# TIEHI/TIELO for osu025, generated by make_tie_cells.py from upstream INVX1.
VERSION 5.4 ;
NAMESCASESENSITIVE ON ;
BUSBITCHARS "[]" ;
DIVIDERCHAR "/" ;

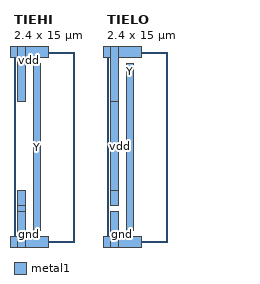
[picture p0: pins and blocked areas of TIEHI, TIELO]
MACRO TIEHI
  CLASS  CORE ;
  FOREIGN TIEHI 0.000 0.000 ;
  ORIGIN 0.000 0.000 ;
  SIZE 2.400 BY 15.000 ;
  SYMMETRY X Y  ;
  SITE core ;
  PIN gnd
    DIRECTION INOUT ;
    USE GROUND ;
    SHAPE ABUTMENT ;
    PORT
      LAYER metal1 ;
        RECT 0.300 2.850 0.900 4.050 ;
        RECT 0.300 2.400 0.900 2.850 ;
        RECT 0.300 -0.450 0.900 2.400 ;
        RECT -0.300 -0.450 2.700 0.450 ;
    END
  END gnd
  PIN Y
    DIRECTION OUTPUT ;
    PORT
      LAYER metal1 ;
        RECT 1.500 0.900 2.100 14.100 ;
    END
  END Y
  PIN vdd
    DIRECTION INOUT ;
    USE POWER ;
    SHAPE ABUTMENT ;
    PORT
      LAYER metal1 ;
        RECT 0.300 11.100 0.900 15.450 ;
        RECT -0.300 14.550 2.700 15.450 ;
    END
  END vdd
END TIEHI

MACRO TIELO
  CLASS  CORE ;
  FOREIGN TIELO 0.000 0.000 ;
  ORIGIN 0.000 0.000 ;
  SIZE 2.400 BY 15.000 ;
  SYMMETRY X Y  ;
  SITE core ;
  PIN gnd
    DIRECTION INOUT ;
    USE GROUND ;
    SHAPE ABUTMENT ;
    PORT
      LAYER metal1 ;
        RECT 0.300 -0.450 0.900 2.400 ;
        RECT -0.300 -0.450 2.700 0.450 ;
    END
  END gnd
  PIN Y
    DIRECTION OUTPUT ;
    PORT
      LAYER metal1 ;
        RECT 1.500 0.900 2.100 14.100 ;
    END
  END Y
  PIN vdd
    DIRECTION INOUT ;
    USE POWER ;
    SHAPE ABUTMENT ;
    PORT
      LAYER metal1 ;
        RECT 0.300 2.850 0.900 4.050 ;
        RECT 0.300 4.050 0.900 11.100 ;
        RECT 0.300 11.100 0.900 15.450 ;
        RECT -0.300 14.550 2.700 15.450 ;
    END
  END vdd
END TIELO

END LIBRARY
